VERSION 5.8 ;
BUSBITCHARS "[]" ;
DIVIDERCHAR "/" ;
UNITS
    DATABASE MICRONS 1000 ;
END UNITS

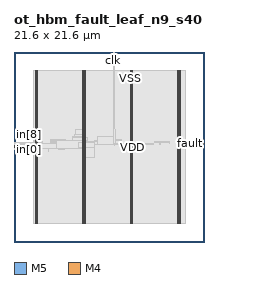
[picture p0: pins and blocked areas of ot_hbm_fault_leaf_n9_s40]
MACRO ot_hbm_fault_leaf_n9_s40
  FOREIGN ot_hbm_fault_leaf_n9_s40 0 0 ;
  CLASS BLOCK ;
  SIZE 21.6 BY 21.6 ;
  PIN clk
    DIRECTION INPUT ;
    USE SIGNAL ;
    PORT
      LAYER M5 ;
        RECT  11.28 21.516 11.304 21.6 ;
    END
  END clk
  PIN fault
    DIRECTION OUTPUT ;
    USE SIGNAL ;
    PORT
      LAYER M4 ;
        RECT  21.516 11.184 21.6 11.208 ;
    END
    PORT
      LAYER M4 ;
        RECT  18.904 11.184 21.564 11.208 ;
    END
  END fault
  PIN in[0]
    DIRECTION INPUT ;
    USE SIGNAL ;
    PORT
      LAYER M4 ;
        RECT  0 10.512 0.084 10.536 ;
    END
  END in[0]
  PIN in[1]
    DIRECTION INPUT ;
    USE SIGNAL ;
    PORT
      LAYER M4 ;
        RECT  0 10.608 0.084 10.632 ;
    END
  END in[1]
  PIN in[2]
    DIRECTION INPUT ;
    USE SIGNAL ;
    PORT
      LAYER M4 ;
        RECT  0 10.704 0.084 10.728 ;
    END
  END in[2]
  PIN in[3]
    DIRECTION INPUT ;
    USE SIGNAL ;
    PORT
      LAYER M4 ;
        RECT  0 10.8 0.084 10.824 ;
    END
  END in[3]
  PIN in[4]
    DIRECTION INPUT ;
    USE SIGNAL ;
    PORT
      LAYER M4 ;
        RECT  0 10.896 0.084 10.92 ;
    END
  END in[4]
  PIN in[5]
    DIRECTION INPUT ;
    USE SIGNAL ;
    PORT
      LAYER M4 ;
        RECT  0 10.992 0.084 11.016 ;
    END
  END in[5]
  PIN in[6]
    DIRECTION INPUT ;
    USE SIGNAL ;
    PORT
      LAYER M4 ;
        RECT  0 11.088 0.084 11.112 ;
    END
  END in[6]
  PIN in[7]
    DIRECTION INPUT ;
    USE SIGNAL ;
    PORT
      LAYER M4 ;
        RECT  0 11.184 0.084 11.208 ;
    END
  END in[7]
  PIN in[8]
    DIRECTION INPUT ;
    USE SIGNAL ;
    PORT
      LAYER M4 ;
        RECT  0 11.28 0.084 11.304 ;
    END
  END in[8]
  PIN rst_n
    DIRECTION INPUT ;
    USE SIGNAL ;
    PORT
      LAYER M5 ;
        RECT  11.376 21.516 11.4 21.6 ;
    END
  END rst_n
  PIN VDD
    DIRECTION INOUT ;
    USE POWER ;
    PORT
      LAYER M5 ;
        RECT  18.792 2.151 18.912 19.449 ;
        RECT  13.392 2.151 13.512 19.449 ;
        RECT  7.992 2.151 8.112 19.449 ;
        RECT  2.592 2.151 2.712 19.449 ;
    END
  END VDD
  PIN VSS
    DIRECTION INOUT ;
    USE GROUND ;
    PORT
      LAYER M5 ;
        RECT  18.6 2.137 18.72 19.463 ;
        RECT  13.2 2.137 13.32 19.463 ;
        RECT  7.8 2.137 7.92 19.463 ;
        RECT  2.4 2.137 2.52 19.463 ;
    END
  END VSS
  # OT_OBS_CLOSED layer=M5 d_um=1.536 added=0
  OBS
    LAYER RVTN ;
     RECT  2.16 2.16 19.44 2.295 ;
     RECT  2.16 2.565 19.44 2.835 ;
     RECT  2.16 3.105 19.44 3.375 ;
     RECT  2.16 3.645 19.44 3.915 ;
     RECT  2.16 4.185 19.44 4.455 ;
     RECT  2.16 4.725 19.44 4.995 ;
     RECT  2.16 5.265 19.44 5.535 ;
     RECT  2.16 5.805 19.44 6.075 ;
     RECT  2.16 6.345 19.44 6.615 ;
     RECT  2.16 6.885 19.44 7.155 ;
     RECT  2.16 7.425 19.44 7.695 ;
     RECT  2.16 7.965 19.44 8.235 ;
     RECT  2.16 8.505 19.44 8.775 ;
     RECT  2.16 9.045 19.44 9.315 ;
     RECT  2.16 9.585 19.44 9.855 ;
     RECT  2.16 10.125 19.44 10.395 ;
     RECT  2.16 10.665 19.44 10.935 ;
     RECT  2.16 11.205 19.44 11.475 ;
     RECT  2.16 11.745 19.44 12.015 ;
     RECT  2.16 12.285 19.44 12.555 ;
     RECT  2.16 12.825 19.44 13.095 ;
     RECT  2.16 13.365 19.44 13.635 ;
     RECT  2.16 13.905 19.44 14.175 ;
     RECT  2.16 14.445 19.44 14.715 ;
     RECT  2.16 14.985 19.44 15.255 ;
     RECT  2.16 15.525 19.44 15.795 ;
     RECT  2.16 16.065 19.44 16.335 ;
     RECT  2.16 16.605 19.44 16.875 ;
     RECT  2.16 17.145 19.44 17.415 ;
     RECT  2.16 17.685 19.44 17.955 ;
     RECT  2.16 18.225 19.44 18.495 ;
     RECT  2.16 18.765 19.44 19.035 ;
     RECT  2.16 19.305 19.44 19.44 ;
    LAYER RVTP ;
     RECT  2.16 2.295 19.44 2.565 ;
     RECT  2.16 2.835 19.44 3.105 ;
     RECT  2.16 3.375 19.44 3.645 ;
     RECT  2.16 3.915 19.44 4.185 ;
     RECT  2.16 4.455 19.44 4.725 ;
     RECT  2.16 4.995 19.44 5.265 ;
     RECT  2.16 5.535 19.44 5.805 ;
     RECT  2.16 6.075 19.44 6.345 ;
     RECT  2.16 6.615 19.44 6.885 ;
     RECT  2.16 7.155 19.44 7.425 ;
     RECT  2.16 7.695 19.44 7.965 ;
     RECT  2.16 8.235 19.44 8.505 ;
     RECT  2.16 8.775 19.44 9.045 ;
     RECT  2.16 9.315 19.44 9.585 ;
     RECT  2.16 9.855 19.44 10.125 ;
     RECT  2.16 10.395 19.44 10.665 ;
     RECT  2.16 10.935 19.44 11.205 ;
     RECT  2.16 11.475 19.44 11.745 ;
     RECT  2.16 12.015 19.44 12.285 ;
     RECT  2.16 12.555 19.44 12.825 ;
     RECT  2.16 13.095 19.44 13.365 ;
     RECT  2.16 13.635 19.44 13.905 ;
     RECT  2.16 14.175 19.44 14.445 ;
     RECT  2.16 14.715 19.44 14.985 ;
     RECT  2.16 15.255 19.44 15.525 ;
     RECT  2.16 15.795 19.44 16.065 ;
     RECT  2.16 16.335 19.44 16.605 ;
     RECT  2.16 16.875 19.44 17.145 ;
     RECT  2.16 17.415 19.44 17.685 ;
     RECT  2.16 17.955 19.44 18.225 ;
     RECT  2.16 18.495 19.44 18.765 ;
     RECT  2.16 19.035 19.44 19.305 ;
    LAYER M1 ;
     RECT  2.16 2.151 19.44 19.449 ;
    LAYER M2 ;
     RECT  2.16 2.151 19.44 19.449 ;
    LAYER M3 ;
     RECT  2.415 2.143 2.505 2.413 ;
     RECT  7.815 2.143 7.905 2.413 ;
     RECT  13.215 2.143 13.305 2.413 ;
     RECT  18.615 2.143 18.705 2.413 ;
     RECT  8.928 9.625 8.946 9.661 ;
     RECT  8.928 9.661 9.126 9.959 ;
     RECT  8.928 9.959 8.946 9.965 ;
     RECT  7.815 2.413 8.097 10.471 ;
     RECT  2.415 2.413 2.697 10.507 ;
     RECT  2.412 10.507 2.697 10.597 ;
     RECT  3.96 10.327 3.978 10.625 ;
     RECT  5.004 10.471 5.706 10.633 ;
     RECT  7.815 10.471 8.19 10.633 ;
     RECT  2.34 10.597 2.697 10.669 ;
     RECT  3.996 10.633 4.194 10.669 ;
     RECT  5.004 10.633 5.814 10.669 ;
     RECT  6.84 10.651 6.858 10.669 ;
     RECT  7.815 10.633 8.262 10.669 ;
     RECT  6.84 10.669 8.262 10.741 ;
     RECT  0.144 10.651 0.162 10.829 ;
     RECT  6.84 10.741 8.298 10.831 ;
     RECT  2.34 10.669 3.258 10.867 ;
     RECT  3.996 10.669 5.814 10.903 ;
     RECT  6.84 10.831 8.982 10.903 ;
     RECT  3.996 10.903 8.982 11.129 ;
     RECT  15.84 11.128 15.858 11.165 ;
     RECT  11.412 11.011 11.43 11.173 ;
     RECT  11.412 11.173 11.574 11.201 ;
     RECT  2.304 10.867 3.258 11.275 ;
     RECT  4.104 11.129 8.982 11.281 ;
     RECT  16.596 11.137 16.614 11.281 ;
     RECT  17.676 11.245 17.694 11.281 ;
     RECT  4.104 11.281 9.126 11.323 ;
     RECT  16.02 11.281 17.694 11.399 ;
     RECT  4.104 11.323 9.666 11.435 ;
     RECT  16.596 11.399 16.614 11.435 ;
     RECT  2.268 11.275 3.258 11.471 ;
     RECT  2.268 11.471 2.697 11.507 ;
     RECT  4.104 11.435 8.37 11.507 ;
     RECT  9.108 11.435 9.666 11.507 ;
     RECT  11.556 11.201 11.574 11.515 ;
     RECT  9.54 11.507 9.666 11.579 ;
     RECT  4.104 11.507 5.85 11.597 ;
     RECT  4.104 11.597 4.698 11.669 ;
     RECT  11.556 11.515 12.258 11.669 ;
     RECT  4.572 11.669 4.59 11.705 ;
     RECT  5.508 11.597 5.526 11.705 ;
     RECT  6.624 11.507 8.37 11.849 ;
     RECT  6.624 11.849 8.154 11.975 ;
     RECT  9.54 11.579 9.558 11.981 ;
     RECT  6.912 11.975 8.154 12.209 ;
     RECT  7.02 12.209 8.097 12.749 ;
     RECT  11.556 11.669 11.574 12.749 ;
     RECT  7.02 12.749 7.038 12.785 ;
     RECT  11.376 12.865 11.394 13.085 ;
     RECT  2.415 11.507 2.697 19.187 ;
     RECT  7.815 12.749 8.097 19.187 ;
     RECT  13.215 2.413 13.497 19.187 ;
     RECT  18.615 2.413 18.897 19.187 ;
     RECT  2.415 19.187 2.505 19.457 ;
     RECT  7.815 19.187 7.905 19.457 ;
     RECT  13.215 19.187 13.305 19.457 ;
     RECT  18.615 19.187 18.705 19.457 ;
    LAYER M4 ;
     RECT  0.084 10.512 2.408 10.536 ;
     RECT  0.06 10.536 2.408 10.608 ;
     RECT  0.084 10.608 2.408 10.632 ;
     RECT  0.06 10.632 2.408 10.704 ;
     RECT  0.084 10.704 2.408 10.728 ;
     RECT  0.06 10.728 2.408 10.8 ;
     RECT  0.084 10.8 2.408 10.824 ;
     RECT  0.06 10.824 2.408 10.896 ;
     RECT  0.084 10.896 2.408 10.92 ;
     RECT  0.06 10.92 2.408 10.992 ;
     RECT  0.084 10.992 2.408 11.016 ;
     RECT  0.06 11.016 2.408 11.088 ;
     RECT  0.084 11.088 2.408 11.112 ;
     RECT  0.06 11.112 2.408 11.184 ;
     RECT  0.084 11.184 2.408 11.208 ;
     RECT  0.06 11.208 2.408 11.28 ;
     RECT  0.084 11.28 2.408 11.304 ;
     RECT  2.408 2.148 2.512 19.452 ;
     RECT  2.512 2.418 2.704 19.182 ;
     RECT  2.704 10.656 4.813 11.208 ;
     RECT  4.813 10.656 7.808 11.592 ;
     RECT  7.808 2.148 7.912 19.452 ;
     RECT  7.912 2.418 8.104 19.182 ;
     RECT  8.104 9.648 8.273 11.448 ;
     RECT  8.273 9.648 8.963 9.96 ;
     RECT  8.963 9.648 9.107 9.672 ;
     RECT  8.273 11.136 9.529 11.448 ;
     RECT  9.529 11.136 11.315 11.976 ;
     RECT  11.365 13.056 11.449 13.08 ;
     RECT  11.315 11.136 13.208 11.16 ;
     RECT  13.208 2.148 13.312 19.452 ;
     RECT  13.312 2.418 13.504 19.182 ;
     RECT  13.504 11.136 15.869 11.16 ;
     RECT  18.608 2.148 18.712 19.452 ;
     RECT  18.712 2.418 18.904 19.182 ;
    LAYER M5 ;
     RECT  2.4 2.137 2.52 2.151 ;
     RECT  7.8 2.137 7.92 2.151 ;
     RECT  13.2 2.137 13.32 2.151 ;
     RECT  18.6 2.137 18.72 2.151 ;
     RECT  7.8 2.151 8.112 9.637 ;
     RECT  7.8 9.637 9.096 10.693 ;
     RECT  7.344 10.693 9.096 11.315 ;
     RECT  7.8 11.315 9.096 11.459 ;
     RECT  11.28 11.941 11.304 13.045 ;
     RECT  2.4 2.151 2.712 19.449 ;
     RECT  7.8 11.459 8.112 19.449 ;
     RECT  13.2 2.151 13.512 19.449 ;
     RECT  18.6 2.151 18.912 19.449 ;
     RECT  2.4 19.449 2.52 19.463 ;
     RECT  7.8 19.449 7.92 19.463 ;
     RECT  13.2 19.449 13.32 19.463 ;
     RECT  18.6 19.449 18.72 19.463 ;
     RECT  11.28 13.045 11.4 21.516 ;
     RECT  11.304 21.516 11.376 21.584 ;
  END
END ot_hbm_fault_leaf_n9_s40
END LIBRARY
